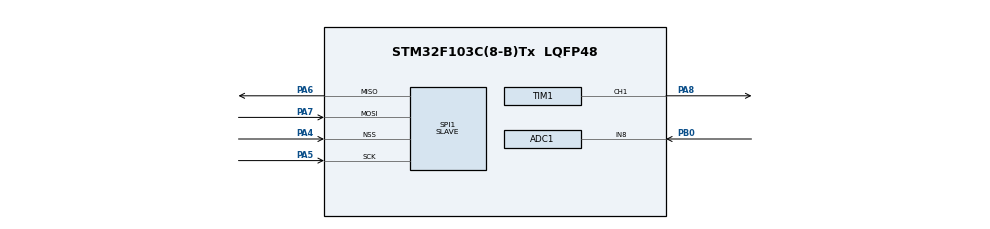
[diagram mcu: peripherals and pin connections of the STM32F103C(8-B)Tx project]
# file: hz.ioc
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ADC1.Channel-0\#ChannelRegularConversion=ADC_CHANNEL_8
ADC1.ContinuousConvMode=ENABLE
ADC1.NbrOfConversionFlag=1
ADC1.Rank-0\#ChannelRegularConversion=1
ADC1.SamplingTime-0\#ChannelRegularConversion=ADC_SAMPLETIME_1CYCLE_5
ADC1.master=1
Dma.ADC1.0.Direction=DMA_PERIPH_TO_MEMORY
Dma.ADC1.0.Instance=DMA1_Channel1
Dma.ADC1.0.MemDataAlignment=DMA_MDATAALIGN_HALFWORD
Dma.ADC1.0.MemInc=DMA_MINC_ENABLE
Dma.ADC1.0.Mode=DMA_CIRCULAR
Dma.ADC1.0.PeriphDataAlignment=DMA_PDATAALIGN_HALFWORD
Dma.ADC1.0.PeriphInc=DMA_PINC_DISABLE
Dma.ADC1.0.Priority=DMA_PRIORITY_HIGH
Dma.Request0=ADC1
Mcu.Family=STM32F1
Mcu.Name=STM32F103C(8-B)Tx
Mcu.Package=LQFP48
NVIC.DMA1_Channel1_IRQn=true\:0\:0\:false\:false\:true\:false\:true\:true
NVIC.PriorityGroup=NVIC_PRIORITYGROUP_4
PA13.Mode=Serial_Wire
PA13.Signal=SYS_JTMS-SWDIO
PA14.Mode=Serial_Wire
PA14.Signal=SYS_JTCK-SWCLK
PA4.Mode=NSS_Signal_Hard_Input
PA4.Signal=SPI1_NSS
PA5.Mode=Full_Duplex_Slave
PA5.Signal=SPI1_SCK
PA6.Mode=Full_Duplex_Slave
PA6.Signal=SPI1_MISO
PA7.Mode=Full_Duplex_Slave
PA7.Signal=SPI1_MOSI
PA8.Signal=S_TIM1_CH1
PB0.Signal=ADCx_IN8
ProjectManager.HeapSize=0x200
ProjectManager.StackSize=0x400
ProjectManager.TargetToolchain=STM32CubeIDE
RCC.APB1Freq_Value=8000000
RCC.APB2Freq_Value=8000000
SH.ADCx_IN8.0=ADC1_IN8,IN8
SH.S_TIM1_CH1.0=TIM1_CH1,PWM Generation1 CH1
SPI1.Direction=SPI_DIRECTION_2LINES
SPI1.Mode=SPI_MODE_SLAVE
SPI1.VirtualNSS=VM_NSSHARD
SPI1.VirtualType=VM_SLAVE
TIM1.Channel-PWM\ Generation1\ CH1=TIM_CHANNEL_1
TIM1.Period=999
TIM1.Prescaler=71
TIM1.Pulse-PWM\ Generation1\ CH1=500
board=custom

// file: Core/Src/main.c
/* USER CODE BEGIN Header */
/**
  ******************************************************************************
  * @file           : main.c
  * @brief          : STM32 Oscilloscope - Fixed version with Timer GPIO init
  ******************************************************************************
  */
/* USER CODE END Header */
#include "main.h"

ADC_HandleTypeDef hadc1;
DMA_HandleTypeDef hdma_adc1;
SPI_HandleTypeDef hspi1;
TIM_HandleTypeDef htim1;

/* USER CODE BEGIN PV */
#define BUFFER_SIZE 1024
uint16_t adc_buffer[BUFFER_SIZE];
volatile uint8_t data_ready = 0;
uint32_t loop_counter = 0;
/* USER CODE END PV */

void SystemClock_Config(void);
static void MX_GPIO_Init(void);
static void MX_DMA_Init(void);
static void MX_ADC1_Init(void);
static void MX_SPI1_Init(void);
static void MX_TIM1_Init(void);

/* USER CODE BEGIN 0 */
void HAL_ADC_ConvCpltCallback(ADC_HandleTypeDef* hadc) {
  data_ready = 1;
}
/* USER CODE END 0 */

int main(void)
{
  HAL_Init();
  SystemClock_Config();
  MX_GPIO_Init();
  MX_DMA_Init();
  MX_ADC1_Init();
  MX_SPI1_Init();
  MX_TIM1_Init();

  /* USER CODE BEGIN 2 */

  // Enable Timer1 and GPIO clocks
  __HAL_RCC_TIM1_CLK_ENABLE();
  __HAL_RCC_GPIOA_CLK_ENABLE();
  __HAL_RCC_GPIOC_CLK_ENABLE();

  // Configure PA8 for TIM1_CH1 (PWM output)
  GPIO_InitTypeDef GPIO_InitStruct = {0};
  GPIO_InitStruct.Pin = GPIO_PIN_8;
  GPIO_InitStruct.Mode = GPIO_MODE_AF_PP;
  GPIO_InitStruct.Pull = GPIO_NOPULL;
  GPIO_InitStruct.Speed = GPIO_SPEED_FREQ_HIGH;
  HAL_GPIO_Init(GPIOA, &GPIO_InitStruct);

  // Configure PC13 for LED
  GPIO_InitStruct.Pin = GPIO_PIN_13;
  GPIO_InitStruct.Mode = GPIO_MODE_OUTPUT_PP;
  GPIO_InitStruct.Speed = GPIO_SPEED_FREQ_LOW;
  HAL_GPIO_Init(GPIOC, &GPIO_InitStruct);

  // Start PWM
  HAL_TIM_PWM_Start(&htim1, TIM_CHANNEL_1);

  // Start ADC with DMA
  HAL_ADC_Start_DMA(&hadc1, (uint32_t*)adc_buffer, BUFFER_SIZE);

  // Flash LED 3 times
  for(int i = 0; i < 3; i++) {
    HAL_GPIO_WritePin(GPIOC, GPIO_PIN_13, GPIO_PIN_RESET);
    HAL_Delay(200);
    HAL_GPIO_WritePin(GPIOC, GPIO_PIN_13, GPIO_PIN_SET);
    HAL_Delay(200);
  }

  /* USER CODE END 2 */

  while (1)
  {
    /* USER CODE BEGIN 3 */

    loop_counter++;

    // Blink LED
    if(loop_counter % 10 == 0) {
      HAL_GPIO_TogglePin(GPIOC, GPIO_PIN_13);
    }

    if(data_ready) {
      data_ready = 0;

      // Send data via SPI
      for(uint16_t i = 0; i < BUFFER_SIZE; i++) {
        while(!(SPI1->SR & SPI_SR_TXE));
        SPI1->DR = (uint8_t)(adc_buffer[i] >> 8);

        while(!(SPI1->SR & SPI_SR_TXE));
        SPI1->DR = (uint8_t)(adc_buffer[i] & 0xFF);
      }

      while(SPI1->SR & SPI_SR_BSY);
    }

    HAL_Delay(10);

  }
  /* USER CODE END 3 */
}

void SystemClock_Config(void)
{
  RCC_OscInitTypeDef RCC_OscInitStruct = {0};
  RCC_ClkInitTypeDef RCC_ClkInitStruct = {0};
  RCC_PeriphCLKInitTypeDef PeriphClkInit = {0};

  RCC_OscInitStruct.OscillatorType = RCC_OSCILLATORTYPE_HSI;
  RCC_OscInitStruct.HSIState = RCC_HSI_ON;
  RCC_OscInitStruct.HSICalibrationValue = RCC_HSICALIBRATION_DEFAULT;
  RCC_OscInitStruct.PLL.PLLState = RCC_PLL_ON;
  RCC_OscInitStruct.PLL.PLLSource = RCC_PLLSOURCE_HSI_DIV2;
  RCC_OscInitStruct.PLL.PLLMUL = RCC_PLL_MUL16;
  HAL_RCC_OscConfig(&RCC_OscInitStruct);

  RCC_ClkInitStruct.ClockType = RCC_CLOCKTYPE_HCLK|RCC_CLOCKTYPE_SYSCLK|RCC_CLOCKTYPE_PCLK1|RCC_CLOCKTYPE_PCLK2;
  RCC_ClkInitStruct.SYSCLKSource = RCC_SYSCLKSOURCE_PLLCLK;
  RCC_ClkInitStruct.AHBCLKDivider = RCC_SYSCLK_DIV1;
  RCC_ClkInitStruct.APB1CLKDivider = RCC_HCLK_DIV2;
  RCC_ClkInitStruct.APB2CLKDivider = RCC_HCLK_DIV1;
  HAL_RCC_ClockConfig(&RCC_ClkInitStruct, FLASH_LATENCY_2);

  PeriphClkInit.PeriphClockSelection = RCC_PERIPHCLK_ADC;
  PeriphClkInit.AdcClockSelection = RCC_ADCPCLK2_DIV6;
  HAL_RCCEx_PeriphCLKConfig(&PeriphClkInit);
}

static void MX_ADC1_Init(void)
{
  ADC_ChannelConfTypeDef sConfig = {0};
  hadc1.Instance = ADC1;
  hadc1.Init.ScanConvMode = ADC_SCAN_DISABLE;
  hadc1.Init.ContinuousConvMode = ENABLE;
  hadc1.Init.DiscontinuousConvMode = DISABLE;
  hadc1.Init.ExternalTrigConv = ADC_SOFTWARE_START;
  hadc1.Init.DataAlign = ADC_DATAALIGN_RIGHT;
  hadc1.Init.NbrOfConversion = 1;
  HAL_ADC_Init(&hadc1);
  sConfig.Channel = ADC_CHANNEL_8;
  sConfig.Rank = ADC_REGULAR_RANK_1;
  sConfig.SamplingTime = ADC_SAMPLETIME_239CYCLES_5;
  HAL_ADC_ConfigChannel(&hadc1, &sConfig);
}

static void MX_SPI1_Init(void)
{
  hspi1.Instance = SPI1;
  hspi1.Init.Mode = SPI_MODE_SLAVE;
  hspi1.Init.Direction = SPI_DIRECTION_2LINES;
  hspi1.Init.DataSize = SPI_DATASIZE_8BIT;
  hspi1.Init.CLKPolarity = SPI_POLARITY_LOW;
  hspi1.Init.CLKPhase = SPI_PHASE_1EDGE;
  hspi1.Init.NSS = SPI_NSS_HARD_INPUT;
  hspi1.Init.FirstBit = SPI_FIRSTBIT_MSB;
  hspi1.Init.TIMode = SPI_TIMODE_DISABLE;
  hspi1.Init.CRCCalculation = SPI_CRCCALCULATION_DISABLE;
  hspi1.Init.CRCPolynomial = 10;
  HAL_SPI_Init(&hspi1);
}

static void MX_TIM1_Init(void)
{
  TIM_ClockConfigTypeDef sClockSourceConfig = {0};
  TIM_MasterConfigTypeDef sMasterConfig = {0};
  TIM_OC_InitTypeDef sConfigOC = {0};
  TIM_BreakDeadTimeConfigTypeDef sBreakDeadTimeConfig = {0};

  htim1.Instance = TIM1;
  htim1.Init.Prescaler = 63;
  htim1.Init.CounterMode = TIM_COUNTERMODE_UP;
  htim1.Init.Period = 999;
  htim1.Init.ClockDivision = TIM_CLOCKDIVISION_DIV1;
  htim1.Init.RepetitionCounter = 0;
  htim1.Init.AutoReloadPreload = TIM_AUTORELOAD_PRELOAD_DISABLE;
  HAL_TIM_Base_Init(&htim1);
  sClockSourceConfig.ClockSource = TIM_CLOCKSOURCE_INTERNAL;
  HAL_TIM_ConfigClockSource(&htim1, &sClockSourceConfig);
  HAL_TIM_PWM_Init(&htim1);
  sMasterConfig.MasterOutputTrigger = TIM_TRGO_RESET;
  sMasterConfig.MasterSlaveMode = TIM_MASTERSLAVEMODE_DISABLE;
  HAL_TIMEx_MasterConfigSynchronization(&htim1, &sMasterConfig);
  sConfigOC.OCMode = TIM_OCMODE_PWM1;
  sConfigOC.Pulse = 500;
  sConfigOC.OCPolarity = TIM_OCPOLARITY_HIGH;
  sConfigOC.OCNPolarity = TIM_OCNPOLARITY_HIGH;
  sConfigOC.OCFastMode = TIM_OCFAST_DISABLE;
  sConfigOC.OCIdleState = TIM_OCIDLESTATE_RESET;
  sConfigOC.OCNIdleState = TIM_OCNIDLESTATE_RESET;
  HAL_TIM_PWM_ConfigChannel(&htim1, &sConfigOC, TIM_CHANNEL_1);
  sBreakDeadTimeConfig.OffStateRunMode = TIM_OSSR_DISABLE;
  sBreakDeadTimeConfig.OffStateIDLEMode = TIM_OSSI_DISABLE;
  sBreakDeadTimeConfig.LockLevel = TIM_LOCKLEVEL_OFF;
  sBreakDeadTimeConfig.DeadTime = 0;
  sBreakDeadTimeConfig.BreakState = TIM_BREAK_DISABLE;
  sBreakDeadTimeConfig.BreakPolarity = TIM_BREAKPOLARITY_HIGH;
  sBreakDeadTimeConfig.AutomaticOutput = TIM_AUTOMATICOUTPUT_DISABLE;
  HAL_TIMEx_ConfigBreakDeadTime(&htim1, &sBreakDeadTimeConfig);
}

static void MX_DMA_Init(void)
{
  __HAL_RCC_DMA1_CLK_ENABLE();
  HAL_NVIC_SetPriority(DMA1_Channel1_IRQn, 0, 0);
  HAL_NVIC_EnableIRQ(DMA1_Channel1_IRQn);
}

static void MX_GPIO_Init(void)
{
  __HAL_RCC_GPIOD_CLK_ENABLE();
  __HAL_RCC_GPIOA_CLK_ENABLE();
  __HAL_RCC_GPIOB_CLK_ENABLE();
  __HAL_RCC_GPIOC_CLK_ENABLE();
}

void Error_Handler(void)
{
  __disable_irq();
  while (1) {}
}
